VERSION 5.7 ;
  NOWIREEXTENSIONATPIN ON ;
  DIVIDERCHAR "/" ;
  BUSBITCHARS "[]" ;
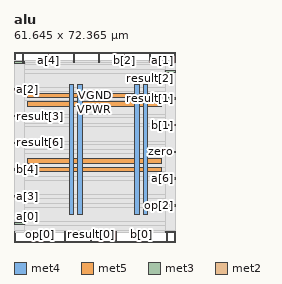
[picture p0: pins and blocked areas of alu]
MACRO alu
  CLASS BLOCK ;
  FOREIGN alu ;
  ORIGIN 0.000 0.000 ;
  SIZE 61.645 BY 72.365 ;
  PIN VGND
    DIRECTION INOUT ;
    USE GROUND ;
    PORT
      LAYER met4 ;
        RECT 24.340 10.640 25.940 60.080 ;
    END
    PORT
      LAYER met4 ;
        RECT 49.340 10.640 50.940 60.080 ;
    END
    PORT
      LAYER met5 ;
        RECT 5.280 30.030 56.360 31.630 ;
    END
    PORT
      LAYER met5 ;
        RECT 5.280 55.030 56.360 56.630 ;
    END
  END VGND
  PIN VPWR
    DIRECTION INOUT ;
    USE POWER ;
    PORT
      LAYER met4 ;
        RECT 21.040 10.640 22.640 60.080 ;
    END
    PORT
      LAYER met4 ;
        RECT 46.040 10.640 47.640 60.080 ;
    END
    PORT
      LAYER met5 ;
        RECT 5.280 26.730 56.360 28.330 ;
    END
    PORT
      LAYER met5 ;
        RECT 5.280 51.730 56.360 53.330 ;
    END
  END VPWR
  PIN a[0]
    DIRECTION INPUT ;
    USE SIGNAL ;
    ANTENNAGATEAREA 0.213000 ;
    PORT
      LAYER met3 ;
        RECT 0.000 6.840 4.000 7.440 ;
    END
  END a[0]
  PIN a[1]
    DIRECTION INPUT ;
    USE SIGNAL ;
    ANTENNAGATEAREA 0.213000 ;
    PORT
      LAYER met2 ;
        RECT 61.270 68.365 61.550 72.365 ;
    END
  END a[1]
  PIN a[2]
    DIRECTION INPUT ;
    USE SIGNAL ;
    ANTENNAGATEAREA 0.159000 ;
    PORT
      LAYER met3 ;
        RECT 0.000 57.840 4.000 58.440 ;
    END
  END a[2]
  PIN a[3]
    DIRECTION INPUT ;
    USE SIGNAL ;
    ANTENNAGATEAREA 0.159000 ;
    PORT
      LAYER met3 ;
        RECT 0.000 17.040 4.000 17.640 ;
    END
  END a[3]
  PIN a[4]
    DIRECTION INPUT ;
    USE SIGNAL ;
    ANTENNAGATEAREA 0.213000 ;
    PORT
      LAYER met2 ;
        RECT 12.970 68.365 13.250 72.365 ;
    END
  END a[4]
  PIN a[5]
    DIRECTION INPUT ;
    USE SIGNAL ;
    ANTENNAGATEAREA 0.213000 ;
    PORT
      LAYER met2 ;
        RECT 22.630 68.365 22.910 72.365 ;
    END
  END a[5]
  PIN a[6]
    DIRECTION INPUT ;
    USE SIGNAL ;
    ANTENNAGATEAREA 0.159000 ;
    PORT
      LAYER met3 ;
        RECT 57.645 23.840 61.645 24.440 ;
    END
  END a[6]
  PIN a[7]
    DIRECTION INPUT ;
    USE SIGNAL ;
    ANTENNAGATEAREA 0.213000 ;
    PORT
      LAYER met2 ;
        RECT 51.610 68.365 51.890 72.365 ;
    END
  END a[7]
  PIN b[0]
    DIRECTION INPUT ;
    USE SIGNAL ;
    ANTENNAGATEAREA 0.159000 ;
    PORT
      LAYER met2 ;
        RECT 48.390 0.000 48.670 4.000 ;
    END
  END b[0]
  PIN b[1]
    DIRECTION INPUT ;
    USE SIGNAL ;
    ANTENNAGATEAREA 0.126000 ;
    PORT
      LAYER met3 ;
        RECT 57.645 44.240 61.645 44.840 ;
    END
  END b[1]
  PIN b[2]
    DIRECTION INPUT ;
    USE SIGNAL ;
    ANTENNAGATEAREA 0.213000 ;
    PORT
      LAYER met2 ;
        RECT 41.950 68.365 42.230 72.365 ;
    END
  END b[2]
  PIN b[3]
    DIRECTION INPUT ;
    USE SIGNAL ;
    ANTENNAGATEAREA 0.213000 ;
    PORT
      LAYER met3 ;
        RECT 57.645 3.440 61.645 4.040 ;
    END
  END b[3]
  PIN b[4]
    DIRECTION INPUT ;
    USE SIGNAL ;
    ANTENNAGATEAREA 0.213000 ;
    PORT
      LAYER met3 ;
        RECT 0.000 27.240 4.000 27.840 ;
    END
  END b[4]
  PIN b[5]
    DIRECTION INPUT ;
    USE SIGNAL ;
    ANTENNAGATEAREA 0.213000 ;
    PORT
      LAYER met2 ;
        RECT 3.310 68.365 3.590 72.365 ;
    END
  END b[5]
  PIN b[6]
    DIRECTION INPUT ;
    USE SIGNAL ;
    ANTENNAGATEAREA 0.213000 ;
    PORT
      LAYER met2 ;
        RECT 58.050 0.000 58.330 4.000 ;
    END
  END b[6]
  PIN b[7]
    DIRECTION INPUT ;
    USE SIGNAL ;
    ANTENNAGATEAREA 0.196500 ;
    PORT
      LAYER met2 ;
        RECT 0.090 0.000 0.370 4.000 ;
    END
  END b[7]
  PIN op[0]
    DIRECTION INPUT ;
    USE SIGNAL ;
    ANTENNAGATEAREA 0.247500 ;
    PORT
      LAYER met2 ;
        RECT 9.750 0.000 10.030 4.000 ;
    END
  END op[0]
  PIN op[1]
    DIRECTION INPUT ;
    USE SIGNAL ;
    ANTENNAGATEAREA 0.159000 ;
    PORT
      LAYER met2 ;
        RECT 19.410 0.000 19.690 4.000 ;
    END
  END op[1]
  PIN op[2]
    DIRECTION INPUT ;
    USE SIGNAL ;
    ANTENNAGATEAREA 0.247500 ;
    PORT
      LAYER met3 ;
        RECT 57.645 13.640 61.645 14.240 ;
    END
  END op[2]
  PIN result[0]
    DIRECTION OUTPUT TRISTATE ;
    USE SIGNAL ;
    ANTENNADIFFAREA 0.795200 ;
    PORT
      LAYER met2 ;
        RECT 29.070 0.000 29.350 4.000 ;
    END
  END result[0]
  PIN result[1]
    DIRECTION OUTPUT TRISTATE ;
    USE SIGNAL ;
    ANTENNADIFFAREA 0.795200 ;
    PORT
      LAYER met3 ;
        RECT 57.645 54.440 61.645 55.040 ;
    END
  END result[1]
  PIN result[2]
    DIRECTION OUTPUT TRISTATE ;
    USE SIGNAL ;
    ANTENNADIFFAREA 0.795200 ;
    PORT
      LAYER met3 ;
        RECT 57.645 64.640 61.645 65.240 ;
    END
  END result[2]
  PIN result[3]
    DIRECTION OUTPUT TRISTATE ;
    USE SIGNAL ;
    ANTENNADIFFAREA 0.795200 ;
    PORT
      LAYER met3 ;
        RECT 0.000 47.640 4.000 48.240 ;
    END
  END result[3]
  PIN result[4]
    DIRECTION OUTPUT TRISTATE ;
    USE SIGNAL ;
    ANTENNADIFFAREA 0.795200 ;
    PORT
      LAYER met2 ;
        RECT 32.290 68.365 32.570 72.365 ;
    END
  END result[4]
  PIN result[5]
    DIRECTION OUTPUT TRISTATE ;
    USE SIGNAL ;
    ANTENNADIFFAREA 0.795200 ;
    PORT
      LAYER met2 ;
        RECT 38.730 0.000 39.010 4.000 ;
    END
  END result[5]
  PIN result[6]
    DIRECTION OUTPUT TRISTATE ;
    USE SIGNAL ;
    ANTENNADIFFAREA 0.795200 ;
    PORT
      LAYER met3 ;
        RECT 0.000 37.440 4.000 38.040 ;
    END
  END result[6]
  PIN result[7]
    DIRECTION OUTPUT TRISTATE ;
    USE SIGNAL ;
    ANTENNADIFFAREA 0.795200 ;
    PORT
      LAYER met3 ;
        RECT 0.000 68.040 4.000 68.640 ;
    END
  END result[7]
  PIN zero
    DIRECTION OUTPUT TRISTATE ;
    USE SIGNAL ;
    ANTENNADIFFAREA 1.336500 ;
    PORT
      LAYER met3 ;
        RECT 57.645 34.040 61.645 34.640 ;
    END
  END zero
  OBS
      LAYER li1 ;
        RECT 5.520 10.795 56.120 59.925 ;
      LAYER met1 ;
        RECT 0.070 10.640 61.570 60.080 ;
      LAYER met2 ;
        RECT 0.100 68.085 3.030 69.090 ;
        RECT 3.870 68.085 12.690 69.090 ;
        RECT 13.530 68.085 22.350 69.090 ;
        RECT 23.190 68.085 32.010 69.090 ;
        RECT 32.850 68.085 41.670 69.090 ;
        RECT 42.510 68.085 51.330 69.090 ;
        RECT 52.170 68.085 60.990 69.090 ;
        RECT 0.100 4.280 61.540 68.085 ;
        RECT 0.650 3.555 9.470 4.280 ;
        RECT 10.310 3.555 19.130 4.280 ;
        RECT 19.970 3.555 28.790 4.280 ;
        RECT 29.630 3.555 38.450 4.280 ;
        RECT 39.290 3.555 48.110 4.280 ;
        RECT 48.950 3.555 57.770 4.280 ;
        RECT 58.610 3.555 61.540 4.280 ;
      LAYER met3 ;
        RECT 4.400 67.640 57.645 68.490 ;
        RECT 4.000 65.640 57.645 67.640 ;
        RECT 4.000 64.240 57.245 65.640 ;
        RECT 4.000 58.840 57.645 64.240 ;
        RECT 4.400 57.440 57.645 58.840 ;
        RECT 4.000 55.440 57.645 57.440 ;
        RECT 4.000 54.040 57.245 55.440 ;
        RECT 4.000 48.640 57.645 54.040 ;
        RECT 4.400 47.240 57.645 48.640 ;
        RECT 4.000 45.240 57.645 47.240 ;
        RECT 4.000 43.840 57.245 45.240 ;
        RECT 4.000 38.440 57.645 43.840 ;
        RECT 4.400 37.040 57.645 38.440 ;
        RECT 4.000 35.040 57.645 37.040 ;
        RECT 4.000 33.640 57.245 35.040 ;
        RECT 4.000 28.240 57.645 33.640 ;
        RECT 4.400 26.840 57.645 28.240 ;
        RECT 4.000 24.840 57.645 26.840 ;
        RECT 4.000 23.440 57.245 24.840 ;
        RECT 4.000 18.040 57.645 23.440 ;
        RECT 4.400 16.640 57.645 18.040 ;
        RECT 4.000 14.640 57.645 16.640 ;
        RECT 4.000 13.240 57.245 14.640 ;
        RECT 4.000 7.840 57.645 13.240 ;
        RECT 4.400 6.440 57.645 7.840 ;
        RECT 4.000 4.440 57.645 6.440 ;
        RECT 4.000 3.575 57.245 4.440 ;
  END
END alu
END LIBRARY

